VERSION 5.7 ;
BUSBITCHARS "[]" ;
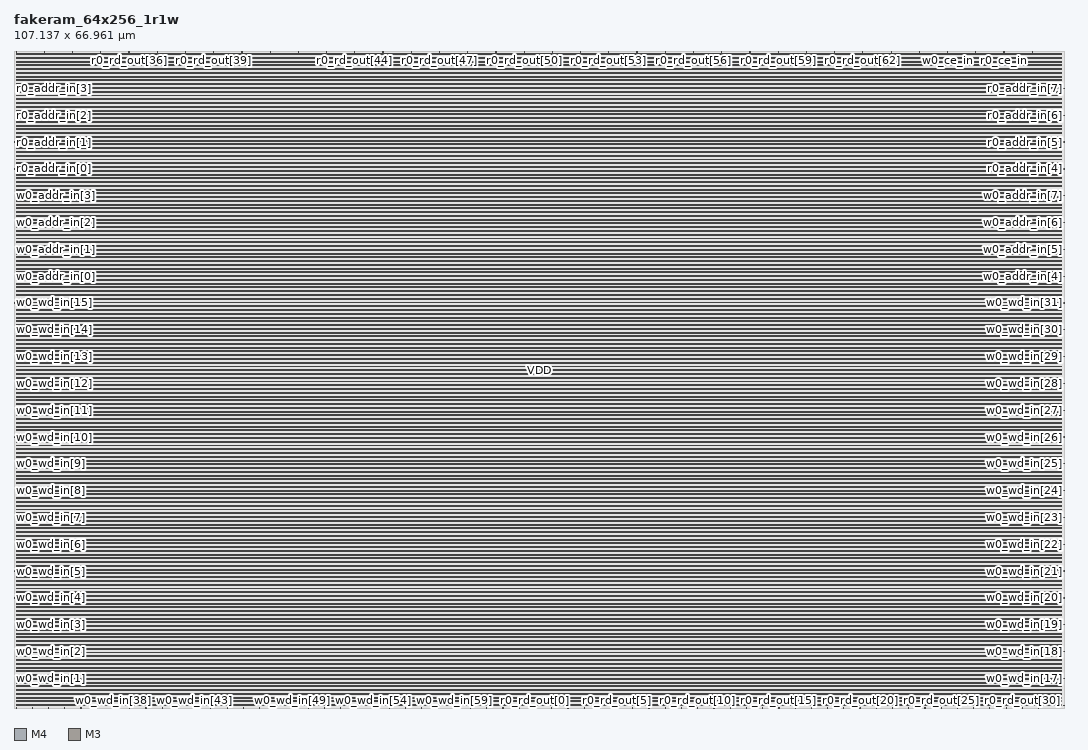
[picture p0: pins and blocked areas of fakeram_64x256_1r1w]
MACRO fakeram_64x256_1r1w
  FOREIGN fakeram_64x256_1r1w 0 0 ;
  SYMMETRY X Y R90 ;
  SIZE 107.137 BY 66.961 ;
  CLASS BLOCK ;
  PIN w0_wd_in[0]
    DIRECTION INPUT ;
    USE SIGNAL ;
    SHAPE ABUTMENT ;
    PORT
      LAYER M4 ;
      RECT 0.000 0.276 0.072 0.300 ;
    END
  END w0_wd_in[0]
  PIN w0_wd_in[1]
    DIRECTION INPUT ;
    USE SIGNAL ;
    SHAPE ABUTMENT ;
    PORT
      LAYER M4 ;
      RECT 0.000 3.012 0.072 3.036 ;
    END
  END w0_wd_in[1]
  PIN w0_wd_in[2]
    DIRECTION INPUT ;
    USE SIGNAL ;
    SHAPE ABUTMENT ;
    PORT
      LAYER M4 ;
      RECT 0.000 5.748 0.072 5.772 ;
    END
  END w0_wd_in[2]
  PIN w0_wd_in[3]
    DIRECTION INPUT ;
    USE SIGNAL ;
    SHAPE ABUTMENT ;
    PORT
      LAYER M4 ;
      RECT 0.000 8.484 0.072 8.508 ;
    END
  END w0_wd_in[3]
  PIN w0_wd_in[4]
    DIRECTION INPUT ;
    USE SIGNAL ;
    SHAPE ABUTMENT ;
    PORT
      LAYER M4 ;
      RECT 0.000 11.220 0.072 11.244 ;
    END
  END w0_wd_in[4]
  PIN w0_wd_in[5]
    DIRECTION INPUT ;
    USE SIGNAL ;
    SHAPE ABUTMENT ;
    PORT
      LAYER M4 ;
      RECT 0.000 13.956 0.072 13.980 ;
    END
  END w0_wd_in[5]
  PIN w0_wd_in[6]
    DIRECTION INPUT ;
    USE SIGNAL ;
    SHAPE ABUTMENT ;
    PORT
      LAYER M4 ;
      RECT 0.000 16.692 0.072 16.716 ;
    END
  END w0_wd_in[6]
  PIN w0_wd_in[7]
    DIRECTION INPUT ;
    USE SIGNAL ;
    SHAPE ABUTMENT ;
    PORT
      LAYER M4 ;
      RECT 0.000 19.428 0.072 19.452 ;
    END
  END w0_wd_in[7]
  PIN w0_wd_in[8]
    DIRECTION INPUT ;
    USE SIGNAL ;
    SHAPE ABUTMENT ;
    PORT
      LAYER M4 ;
      RECT 0.000 22.164 0.072 22.188 ;
    END
  END w0_wd_in[8]
  PIN w0_wd_in[9]
    DIRECTION INPUT ;
    USE SIGNAL ;
    SHAPE ABUTMENT ;
    PORT
      LAYER M4 ;
      RECT 0.000 24.900 0.072 24.924 ;
    END
  END w0_wd_in[9]
  PIN w0_wd_in[10]
    DIRECTION INPUT ;
    USE SIGNAL ;
    SHAPE ABUTMENT ;
    PORT
      LAYER M4 ;
      RECT 0.000 27.636 0.072 27.660 ;
    END
  END w0_wd_in[10]
  PIN w0_wd_in[11]
    DIRECTION INPUT ;
    USE SIGNAL ;
    SHAPE ABUTMENT ;
    PORT
      LAYER M4 ;
      RECT 0.000 30.372 0.072 30.396 ;
    END
  END w0_wd_in[11]
  PIN w0_wd_in[12]
    DIRECTION INPUT ;
    USE SIGNAL ;
    SHAPE ABUTMENT ;
    PORT
      LAYER M4 ;
      RECT 0.000 33.108 0.072 33.132 ;
    END
  END w0_wd_in[12]
  PIN w0_wd_in[13]
    DIRECTION INPUT ;
    USE SIGNAL ;
    SHAPE ABUTMENT ;
    PORT
      LAYER M4 ;
      RECT 0.000 35.844 0.072 35.868 ;
    END
  END w0_wd_in[13]
  PIN w0_wd_in[14]
    DIRECTION INPUT ;
    USE SIGNAL ;
    SHAPE ABUTMENT ;
    PORT
      LAYER M4 ;
      RECT 0.000 38.580 0.072 38.604 ;
    END
  END w0_wd_in[14]
  PIN w0_wd_in[15]
    DIRECTION INPUT ;
    USE SIGNAL ;
    SHAPE ABUTMENT ;
    PORT
      LAYER M4 ;
      RECT 0.000 41.316 0.072 41.340 ;
    END
  END w0_wd_in[15]
  PIN w0_wd_in[16]
    DIRECTION INPUT ;
    USE SIGNAL ;
    SHAPE ABUTMENT ;
    PORT
      LAYER M4 ;
      RECT 107.065 0.276 107.137 0.300 ;
    END
  END w0_wd_in[16]
  PIN w0_wd_in[17]
    DIRECTION INPUT ;
    USE SIGNAL ;
    SHAPE ABUTMENT ;
    PORT
      LAYER M4 ;
      RECT 107.065 3.012 107.137 3.036 ;
    END
  END w0_wd_in[17]
  PIN w0_wd_in[18]
    DIRECTION INPUT ;
    USE SIGNAL ;
    SHAPE ABUTMENT ;
    PORT
      LAYER M4 ;
      RECT 107.065 5.748 107.137 5.772 ;
    END
  END w0_wd_in[18]
  PIN w0_wd_in[19]
    DIRECTION INPUT ;
    USE SIGNAL ;
    SHAPE ABUTMENT ;
    PORT
      LAYER M4 ;
      RECT 107.065 8.484 107.137 8.508 ;
    END
  END w0_wd_in[19]
  PIN w0_wd_in[20]
    DIRECTION INPUT ;
    USE SIGNAL ;
    SHAPE ABUTMENT ;
    PORT
      LAYER M4 ;
      RECT 107.065 11.220 107.137 11.244 ;
    END
  END w0_wd_in[20]
  PIN w0_wd_in[21]
    DIRECTION INPUT ;
    USE SIGNAL ;
    SHAPE ABUTMENT ;
    PORT
      LAYER M4 ;
      RECT 107.065 13.956 107.137 13.980 ;
    END
  END w0_wd_in[21]
  PIN w0_wd_in[22]
    DIRECTION INPUT ;
    USE SIGNAL ;
    SHAPE ABUTMENT ;
    PORT
      LAYER M4 ;
      RECT 107.065 16.692 107.137 16.716 ;
    END
  END w0_wd_in[22]
  PIN w0_wd_in[23]
    DIRECTION INPUT ;
    USE SIGNAL ;
    SHAPE ABUTMENT ;
    PORT
      LAYER M4 ;
      RECT 107.065 19.428 107.137 19.452 ;
    END
  END w0_wd_in[23]
  PIN w0_wd_in[24]
    DIRECTION INPUT ;
    USE SIGNAL ;
    SHAPE ABUTMENT ;
    PORT
      LAYER M4 ;
      RECT 107.065 22.164 107.137 22.188 ;
    END
  END w0_wd_in[24]
  PIN w0_wd_in[25]
    DIRECTION INPUT ;
    USE SIGNAL ;
    SHAPE ABUTMENT ;
    PORT
      LAYER M4 ;
      RECT 107.065 24.900 107.137 24.924 ;
    END
  END w0_wd_in[25]
  PIN w0_wd_in[26]
    DIRECTION INPUT ;
    USE SIGNAL ;
    SHAPE ABUTMENT ;
    PORT
      LAYER M4 ;
      RECT 107.065 27.636 107.137 27.660 ;
    END
  END w0_wd_in[26]
  PIN w0_wd_in[27]
    DIRECTION INPUT ;
    USE SIGNAL ;
    SHAPE ABUTMENT ;
    PORT
      LAYER M4 ;
      RECT 107.065 30.372 107.137 30.396 ;
    END
  END w0_wd_in[27]
  PIN w0_wd_in[28]
    DIRECTION INPUT ;
    USE SIGNAL ;
    SHAPE ABUTMENT ;
    PORT
      LAYER M4 ;
      RECT 107.065 33.108 107.137 33.132 ;
    END
  END w0_wd_in[28]
  PIN w0_wd_in[29]
    DIRECTION INPUT ;
    USE SIGNAL ;
    SHAPE ABUTMENT ;
    PORT
      LAYER M4 ;
      RECT 107.065 35.844 107.137 35.868 ;
    END
  END w0_wd_in[29]
  PIN w0_wd_in[30]
    DIRECTION INPUT ;
    USE SIGNAL ;
    SHAPE ABUTMENT ;
    PORT
      LAYER M4 ;
      RECT 107.065 38.580 107.137 38.604 ;
    END
  END w0_wd_in[30]
  PIN w0_wd_in[31]
    DIRECTION INPUT ;
    USE SIGNAL ;
    SHAPE ABUTMENT ;
    PORT
      LAYER M4 ;
      RECT 107.065 41.316 107.137 41.340 ;
    END
  END w0_wd_in[31]
  PIN w0_wd_in[32]
    DIRECTION INPUT ;
    USE SIGNAL ;
    SHAPE ABUTMENT ;
    PORT
      LAYER M3 ;
      RECT 0.207 0.000 0.225 0.054 ;
    END
  END w0_wd_in[32]
  PIN w0_wd_in[33]
    DIRECTION INPUT ;
    USE SIGNAL ;
    SHAPE ABUTMENT ;
    PORT
      LAYER M3 ;
      RECT 1.863 0.000 1.881 0.054 ;
    END
  END w0_wd_in[33]
  PIN w0_wd_in[34]
    DIRECTION INPUT ;
    USE SIGNAL ;
    SHAPE ABUTMENT ;
    PORT
      LAYER M3 ;
      RECT 3.519 0.000 3.537 0.054 ;
    END
  END w0_wd_in[34]
  PIN w0_wd_in[35]
    DIRECTION INPUT ;
    USE SIGNAL ;
    SHAPE ABUTMENT ;
    PORT
      LAYER M3 ;
      RECT 5.175 0.000 5.193 0.054 ;
    END
  END w0_wd_in[35]
  PIN w0_wd_in[36]
    DIRECTION INPUT ;
    USE SIGNAL ;
    SHAPE ABUTMENT ;
    PORT
      LAYER M3 ;
      RECT 6.831 0.000 6.849 0.054 ;
    END
  END w0_wd_in[36]
  PIN w0_wd_in[37]
    DIRECTION INPUT ;
    USE SIGNAL ;
    SHAPE ABUTMENT ;
    PORT
      LAYER M3 ;
      RECT 8.487 0.000 8.505 0.054 ;
    END
  END w0_wd_in[37]
  PIN w0_wd_in[38]
    DIRECTION INPUT ;
    USE SIGNAL ;
    SHAPE ABUTMENT ;
    PORT
      LAYER M3 ;
      RECT 10.143 0.000 10.161 0.054 ;
    END
  END w0_wd_in[38]
  PIN w0_wd_in[39]
    DIRECTION INPUT ;
    USE SIGNAL ;
    SHAPE ABUTMENT ;
    PORT
      LAYER M3 ;
      RECT 11.799 0.000 11.817 0.054 ;
    END
  END w0_wd_in[39]
  PIN w0_wd_in[40]
    DIRECTION INPUT ;
    USE SIGNAL ;
    SHAPE ABUTMENT ;
    PORT
      LAYER M3 ;
      RECT 13.455 0.000 13.473 0.054 ;
    END
  END w0_wd_in[40]
  PIN w0_wd_in[41]
    DIRECTION INPUT ;
    USE SIGNAL ;
    SHAPE ABUTMENT ;
    PORT
      LAYER M3 ;
      RECT 15.111 0.000 15.129 0.054 ;
    END
  END w0_wd_in[41]
  PIN w0_wd_in[42]
    DIRECTION INPUT ;
    USE SIGNAL ;
    SHAPE ABUTMENT ;
    PORT
      LAYER M3 ;
      RECT 16.767 0.000 16.785 0.054 ;
    END
  END w0_wd_in[42]
  PIN w0_wd_in[43]
    DIRECTION INPUT ;
    USE SIGNAL ;
    SHAPE ABUTMENT ;
    PORT
      LAYER M3 ;
      RECT 18.423 0.000 18.441 0.054 ;
    END
  END w0_wd_in[43]
  PIN w0_wd_in[44]
    DIRECTION INPUT ;
    USE SIGNAL ;
    SHAPE ABUTMENT ;
    PORT
      LAYER M3 ;
      RECT 20.079 0.000 20.097 0.054 ;
    END
  END w0_wd_in[44]
  PIN w0_wd_in[45]
    DIRECTION INPUT ;
    USE SIGNAL ;
    SHAPE ABUTMENT ;
    PORT
      LAYER M3 ;
      RECT 21.735 0.000 21.753 0.054 ;
    END
  END w0_wd_in[45]
  PIN w0_wd_in[46]
    DIRECTION INPUT ;
    USE SIGNAL ;
    SHAPE ABUTMENT ;
    PORT
      LAYER M3 ;
      RECT 23.391 0.000 23.409 0.054 ;
    END
  END w0_wd_in[46]
  PIN w0_wd_in[47]
    DIRECTION INPUT ;
    USE SIGNAL ;
    SHAPE ABUTMENT ;
    PORT
      LAYER M3 ;
      RECT 25.047 0.000 25.065 0.054 ;
    END
  END w0_wd_in[47]
  PIN w0_wd_in[48]
    DIRECTION INPUT ;
    USE SIGNAL ;
    SHAPE ABUTMENT ;
    PORT
      LAYER M3 ;
      RECT 26.703 0.000 26.721 0.054 ;
    END
  END w0_wd_in[48]
  PIN w0_wd_in[49]
    DIRECTION INPUT ;
    USE SIGNAL ;
    SHAPE ABUTMENT ;
    PORT
      LAYER M3 ;
      RECT 28.359 0.000 28.377 0.054 ;
    END
  END w0_wd_in[49]
  PIN w0_wd_in[50]
    DIRECTION INPUT ;
    USE SIGNAL ;
    SHAPE ABUTMENT ;
    PORT
      LAYER M3 ;
      RECT 30.015 0.000 30.033 0.054 ;
    END
  END w0_wd_in[50]
  PIN w0_wd_in[51]
    DIRECTION INPUT ;
    USE SIGNAL ;
    SHAPE ABUTMENT ;
    PORT
      LAYER M3 ;
      RECT 31.671 0.000 31.689 0.054 ;
    END
  END w0_wd_in[51]
  PIN w0_wd_in[52]
    DIRECTION INPUT ;
    USE SIGNAL ;
    SHAPE ABUTMENT ;
    PORT
      LAYER M3 ;
      RECT 33.327 0.000 33.345 0.054 ;
    END
  END w0_wd_in[52]
  PIN w0_wd_in[53]
    DIRECTION INPUT ;
    USE SIGNAL ;
    SHAPE ABUTMENT ;
    PORT
      LAYER M3 ;
      RECT 34.983 0.000 35.001 0.054 ;
    END
  END w0_wd_in[53]
  PIN w0_wd_in[54]
    DIRECTION INPUT ;
    USE SIGNAL ;
    SHAPE ABUTMENT ;
    PORT
      LAYER M3 ;
      RECT 36.639 0.000 36.657 0.054 ;
    END
  END w0_wd_in[54]
  PIN w0_wd_in[55]
    DIRECTION INPUT ;
    USE SIGNAL ;
    SHAPE ABUTMENT ;
    PORT
      LAYER M3 ;
      RECT 38.295 0.000 38.313 0.054 ;
    END
  END w0_wd_in[55]
  PIN w0_wd_in[56]
    DIRECTION INPUT ;
    USE SIGNAL ;
    SHAPE ABUTMENT ;
    PORT
      LAYER M3 ;
      RECT 39.951 0.000 39.969 0.054 ;
    END
  END w0_wd_in[56]
  PIN w0_wd_in[57]
    DIRECTION INPUT ;
    USE SIGNAL ;
    SHAPE ABUTMENT ;
    PORT
      LAYER M3 ;
      RECT 41.607 0.000 41.625 0.054 ;
    END
  END w0_wd_in[57]
  PIN w0_wd_in[58]
    DIRECTION INPUT ;
    USE SIGNAL ;
    SHAPE ABUTMENT ;
    PORT
      LAYER M3 ;
      RECT 43.263 0.000 43.281 0.054 ;
    END
  END w0_wd_in[58]
  PIN w0_wd_in[59]
    DIRECTION INPUT ;
    USE SIGNAL ;
    SHAPE ABUTMENT ;
    PORT
      LAYER M3 ;
      RECT 44.919 0.000 44.937 0.054 ;
    END
  END w0_wd_in[59]
  PIN w0_wd_in[60]
    DIRECTION INPUT ;
    USE SIGNAL ;
    SHAPE ABUTMENT ;
    PORT
      LAYER M3 ;
      RECT 46.575 0.000 46.593 0.054 ;
    END
  END w0_wd_in[60]
  PIN w0_wd_in[61]
    DIRECTION INPUT ;
    USE SIGNAL ;
    SHAPE ABUTMENT ;
    PORT
      LAYER M3 ;
      RECT 48.231 0.000 48.249 0.054 ;
    END
  END w0_wd_in[61]
  PIN w0_wd_in[62]
    DIRECTION INPUT ;
    USE SIGNAL ;
    SHAPE ABUTMENT ;
    PORT
      LAYER M3 ;
      RECT 49.887 0.000 49.905 0.054 ;
    END
  END w0_wd_in[62]
  PIN w0_wd_in[63]
    DIRECTION INPUT ;
    USE SIGNAL ;
    SHAPE ABUTMENT ;
    PORT
      LAYER M3 ;
      RECT 51.543 0.000 51.561 0.054 ;
    END
  END w0_wd_in[63]
  PIN r0_rd_out[0]
    DIRECTION OUTPUT ;
    USE SIGNAL ;
    SHAPE ABUTMENT ;
    PORT
      LAYER M3 ;
      RECT 53.199 0.000 53.217 0.054 ;
    END
  END r0_rd_out[0]
  PIN r0_rd_out[1]
    DIRECTION OUTPUT ;
    USE SIGNAL ;
    SHAPE ABUTMENT ;
    PORT
      LAYER M3 ;
      RECT 54.855 0.000 54.873 0.054 ;
    END
  END r0_rd_out[1]
  PIN r0_rd_out[2]
    DIRECTION OUTPUT ;
    USE SIGNAL ;
    SHAPE ABUTMENT ;
    PORT
      LAYER M3 ;
      RECT 56.511 0.000 56.529 0.054 ;
    END
  END r0_rd_out[2]
  PIN r0_rd_out[3]
    DIRECTION OUTPUT ;
    USE SIGNAL ;
    SHAPE ABUTMENT ;
    PORT
      LAYER M3 ;
      RECT 58.167 0.000 58.185 0.054 ;
    END
  END r0_rd_out[3]
  PIN r0_rd_out[4]
    DIRECTION OUTPUT ;
    USE SIGNAL ;
    SHAPE ABUTMENT ;
    PORT
      LAYER M3 ;
      RECT 59.823 0.000 59.841 0.054 ;
    END
  END r0_rd_out[4]
  PIN r0_rd_out[5]
    DIRECTION OUTPUT ;
    USE SIGNAL ;
    SHAPE ABUTMENT ;
    PORT
      LAYER M3 ;
      RECT 61.479 0.000 61.497 0.054 ;
    END
  END r0_rd_out[5]
  PIN r0_rd_out[6]
    DIRECTION OUTPUT ;
    USE SIGNAL ;
    SHAPE ABUTMENT ;
    PORT
      LAYER M3 ;
      RECT 63.135 0.000 63.153 0.054 ;
    END
  END r0_rd_out[6]
  PIN r0_rd_out[7]
    DIRECTION OUTPUT ;
    USE SIGNAL ;
    SHAPE ABUTMENT ;
    PORT
      LAYER M3 ;
      RECT 64.791 0.000 64.809 0.054 ;
    END
  END r0_rd_out[7]
  PIN r0_rd_out[8]
    DIRECTION OUTPUT ;
    USE SIGNAL ;
    SHAPE ABUTMENT ;
    PORT
      LAYER M3 ;
      RECT 66.447 0.000 66.465 0.054 ;
    END
  END r0_rd_out[8]
  PIN r0_rd_out[9]
    DIRECTION OUTPUT ;
    USE SIGNAL ;
    SHAPE ABUTMENT ;
    PORT
      LAYER M3 ;
      RECT 68.103 0.000 68.121 0.054 ;
    END
  END r0_rd_out[9]
  PIN r0_rd_out[10]
    DIRECTION OUTPUT ;
    USE SIGNAL ;
    SHAPE ABUTMENT ;
    PORT
      LAYER M3 ;
      RECT 69.759 0.000 69.777 0.054 ;
    END
  END r0_rd_out[10]
  PIN r0_rd_out[11]
    DIRECTION OUTPUT ;
    USE SIGNAL ;
    SHAPE ABUTMENT ;
    PORT
      LAYER M3 ;
      RECT 71.415 0.000 71.433 0.054 ;
    END
  END r0_rd_out[11]
  PIN r0_rd_out[12]
    DIRECTION OUTPUT ;
    USE SIGNAL ;
    SHAPE ABUTMENT ;
    PORT
      LAYER M3 ;
      RECT 73.071 0.000 73.089 0.054 ;
    END
  END r0_rd_out[12]
  PIN r0_rd_out[13]
    DIRECTION OUTPUT ;
    USE SIGNAL ;
    SHAPE ABUTMENT ;
    PORT
      LAYER M3 ;
      RECT 74.727 0.000 74.745 0.054 ;
    END
  END r0_rd_out[13]
  PIN r0_rd_out[14]
    DIRECTION OUTPUT ;
    USE SIGNAL ;
    SHAPE ABUTMENT ;
    PORT
      LAYER M3 ;
      RECT 76.383 0.000 76.401 0.054 ;
    END
  END r0_rd_out[14]
  PIN r0_rd_out[15]
    DIRECTION OUTPUT ;
    USE SIGNAL ;
    SHAPE ABUTMENT ;
    PORT
      LAYER M3 ;
      RECT 78.039 0.000 78.057 0.054 ;
    END
  END r0_rd_out[15]
  PIN r0_rd_out[16]
    DIRECTION OUTPUT ;
    USE SIGNAL ;
    SHAPE ABUTMENT ;
    PORT
      LAYER M3 ;
      RECT 79.695 0.000 79.713 0.054 ;
    END
  END r0_rd_out[16]
  PIN r0_rd_out[17]
    DIRECTION OUTPUT ;
    USE SIGNAL ;
    SHAPE ABUTMENT ;
    PORT
      LAYER M3 ;
      RECT 81.351 0.000 81.369 0.054 ;
    END
  END r0_rd_out[17]
  PIN r0_rd_out[18]
    DIRECTION OUTPUT ;
    USE SIGNAL ;
    SHAPE ABUTMENT ;
    PORT
      LAYER M3 ;
      RECT 83.007 0.000 83.025 0.054 ;
    END
  END r0_rd_out[18]
  PIN r0_rd_out[19]
    DIRECTION OUTPUT ;
    USE SIGNAL ;
    SHAPE ABUTMENT ;
    PORT
      LAYER M3 ;
      RECT 84.663 0.000 84.681 0.054 ;
    END
  END r0_rd_out[19]
  PIN r0_rd_out[20]
    DIRECTION OUTPUT ;
    USE SIGNAL ;
    SHAPE ABUTMENT ;
    PORT
      LAYER M3 ;
      RECT 86.319 0.000 86.337 0.054 ;
    END
  END r0_rd_out[20]
  PIN r0_rd_out[21]
    DIRECTION OUTPUT ;
    USE SIGNAL ;
    SHAPE ABUTMENT ;
    PORT
      LAYER M3 ;
      RECT 87.975 0.000 87.993 0.054 ;
    END
  END r0_rd_out[21]
  PIN r0_rd_out[22]
    DIRECTION OUTPUT ;
    USE SIGNAL ;
    SHAPE ABUTMENT ;
    PORT
      LAYER M3 ;
      RECT 89.631 0.000 89.649 0.054 ;
    END
  END r0_rd_out[22]
  PIN r0_rd_out[23]
    DIRECTION OUTPUT ;
    USE SIGNAL ;
    SHAPE ABUTMENT ;
    PORT
      LAYER M3 ;
      RECT 91.287 0.000 91.305 0.054 ;
    END
  END r0_rd_out[23]
  PIN r0_rd_out[24]
    DIRECTION OUTPUT ;
    USE SIGNAL ;
    SHAPE ABUTMENT ;
    PORT
      LAYER M3 ;
      RECT 92.943 0.000 92.961 0.054 ;
    END
  END r0_rd_out[24]
  PIN r0_rd_out[25]
    DIRECTION OUTPUT ;
    USE SIGNAL ;
    SHAPE ABUTMENT ;
    PORT
      LAYER M3 ;
      RECT 94.599 0.000 94.617 0.054 ;
    END
  END r0_rd_out[25]
  PIN r0_rd_out[26]
    DIRECTION OUTPUT ;
    USE SIGNAL ;
    SHAPE ABUTMENT ;
    PORT
      LAYER M3 ;
      RECT 96.255 0.000 96.273 0.054 ;
    END
  END r0_rd_out[26]
  PIN r0_rd_out[27]
    DIRECTION OUTPUT ;
    USE SIGNAL ;
    SHAPE ABUTMENT ;
    PORT
      LAYER M3 ;
      RECT 97.911 0.000 97.929 0.054 ;
    END
  END r0_rd_out[27]
  PIN r0_rd_out[28]
    DIRECTION OUTPUT ;
    USE SIGNAL ;
    SHAPE ABUTMENT ;
    PORT
      LAYER M3 ;
      RECT 99.567 0.000 99.585 0.054 ;
    END
  END r0_rd_out[28]
  PIN r0_rd_out[29]
    DIRECTION OUTPUT ;
    USE SIGNAL ;
    SHAPE ABUTMENT ;
    PORT
      LAYER M3 ;
      RECT 101.223 0.000 101.241 0.054 ;
    END
  END r0_rd_out[29]
  PIN r0_rd_out[30]
    DIRECTION OUTPUT ;
    USE SIGNAL ;
    SHAPE ABUTMENT ;
    PORT
      LAYER M3 ;
      RECT 102.879 0.000 102.897 0.054 ;
    END
  END r0_rd_out[30]
  PIN r0_rd_out[31]
    DIRECTION OUTPUT ;
    USE SIGNAL ;
    SHAPE ABUTMENT ;
    PORT
      LAYER M3 ;
      RECT 104.535 0.000 104.553 0.054 ;
    END
  END r0_rd_out[31]
  PIN r0_rd_out[32]
    DIRECTION OUTPUT ;
    USE SIGNAL ;
    SHAPE ABUTMENT ;
    PORT
      LAYER M3 ;
      RECT 0.207 66.907 0.225 66.961 ;
    END
  END r0_rd_out[32]
  PIN r0_rd_out[33]
    DIRECTION OUTPUT ;
    USE SIGNAL ;
    SHAPE ABUTMENT ;
    PORT
      LAYER M3 ;
      RECT 3.087 66.907 3.105 66.961 ;
    END
  END r0_rd_out[33]
  PIN r0_rd_out[34]
    DIRECTION OUTPUT ;
    USE SIGNAL ;
    SHAPE ABUTMENT ;
    PORT
      LAYER M3 ;
      RECT 5.967 66.907 5.985 66.961 ;
    END
  END r0_rd_out[34]
  PIN r0_rd_out[35]
    DIRECTION OUTPUT ;
    USE SIGNAL ;
    SHAPE ABUTMENT ;
    PORT
      LAYER M3 ;
      RECT 8.847 66.907 8.865 66.961 ;
    END
  END r0_rd_out[35]
  PIN r0_rd_out[36]
    DIRECTION OUTPUT ;
    USE SIGNAL ;
    SHAPE ABUTMENT ;
    PORT
      LAYER M3 ;
      RECT 11.727 66.907 11.745 66.961 ;
    END
  END r0_rd_out[36]
  PIN r0_rd_out[37]
    DIRECTION OUTPUT ;
    USE SIGNAL ;
    SHAPE ABUTMENT ;
    PORT
      LAYER M3 ;
      RECT 14.607 66.907 14.625 66.961 ;
    END
  END r0_rd_out[37]
  PIN r0_rd_out[38]
    DIRECTION OUTPUT ;
    USE SIGNAL ;
    SHAPE ABUTMENT ;
    PORT
      LAYER M3 ;
      RECT 17.487 66.907 17.505 66.961 ;
    END
  END r0_rd_out[38]
  PIN r0_rd_out[39]
    DIRECTION OUTPUT ;
    USE SIGNAL ;
    SHAPE ABUTMENT ;
    PORT
      LAYER M3 ;
      RECT 20.367 66.907 20.385 66.961 ;
    END
  END r0_rd_out[39]
  PIN r0_rd_out[40]
    DIRECTION OUTPUT ;
    USE SIGNAL ;
    SHAPE ABUTMENT ;
    PORT
      LAYER M3 ;
      RECT 23.247 66.907 23.265 66.961 ;
    END
  END r0_rd_out[40]
  PIN r0_rd_out[41]
    DIRECTION OUTPUT ;
    USE SIGNAL ;
    SHAPE ABUTMENT ;
    PORT
      LAYER M3 ;
      RECT 26.127 66.907 26.145 66.961 ;
    END
  END r0_rd_out[41]
  PIN r0_rd_out[42]
    DIRECTION OUTPUT ;
    USE SIGNAL ;
    SHAPE ABUTMENT ;
    PORT
      LAYER M3 ;
      RECT 29.007 66.907 29.025 66.961 ;
    END
  END r0_rd_out[42]
  PIN r0_rd_out[43]
    DIRECTION OUTPUT ;
    USE SIGNAL ;
    SHAPE ABUTMENT ;
    PORT
      LAYER M3 ;
      RECT 31.887 66.907 31.905 66.961 ;
    END
  END r0_rd_out[43]
  PIN r0_rd_out[44]
    DIRECTION OUTPUT ;
    USE SIGNAL ;
    SHAPE ABUTMENT ;
    PORT
      LAYER M3 ;
      RECT 34.767 66.907 34.785 66.961 ;
    END
  END r0_rd_out[44]
  PIN r0_rd_out[45]
    DIRECTION OUTPUT ;
    USE SIGNAL ;
    SHAPE ABUTMENT ;
    PORT
      LAYER M3 ;
      RECT 37.647 66.907 37.665 66.961 ;
    END
  END r0_rd_out[45]
  PIN r0_rd_out[46]
    DIRECTION OUTPUT ;
    USE SIGNAL ;
    SHAPE ABUTMENT ;
    PORT
      LAYER M3 ;
      RECT 40.527 66.907 40.545 66.961 ;
    END
  END r0_rd_out[46]
  PIN r0_rd_out[47]
    DIRECTION OUTPUT ;
    USE SIGNAL ;
    SHAPE ABUTMENT ;
    PORT
      LAYER M3 ;
      RECT 43.407 66.907 43.425 66.961 ;
    END
  END r0_rd_out[47]
  PIN r0_rd_out[48]
    DIRECTION OUTPUT ;
    USE SIGNAL ;
    SHAPE ABUTMENT ;
    PORT
      LAYER M3 ;
      RECT 46.287 66.907 46.305 66.961 ;
    END
  END r0_rd_out[48]
  PIN r0_rd_out[49]
    DIRECTION OUTPUT ;
    USE SIGNAL ;
    SHAPE ABUTMENT ;
    PORT
      LAYER M3 ;
      RECT 49.167 66.907 49.185 66.961 ;
    END
  END r0_rd_out[49]
  PIN r0_rd_out[50]
    DIRECTION OUTPUT ;
    USE SIGNAL ;
    SHAPE ABUTMENT ;
    PORT
      LAYER M3 ;
      RECT 52.047 66.907 52.065 66.961 ;
    END
  END r0_rd_out[50]
  PIN r0_rd_out[51]
    DIRECTION OUTPUT ;
    USE SIGNAL ;
    SHAPE ABUTMENT ;
    PORT
      LAYER M3 ;
      RECT 54.927 66.907 54.945 66.961 ;
    END
  END r0_rd_out[51]
  PIN r0_rd_out[52]
    DIRECTION OUTPUT ;
    USE SIGNAL ;
    SHAPE ABUTMENT ;
    PORT
      LAYER M3 ;
      RECT 57.807 66.907 57.825 66.961 ;
    END
  END r0_rd_out[52]
  PIN r0_rd_out[53]
    DIRECTION OUTPUT ;
    USE SIGNAL ;
    SHAPE ABUTMENT ;
    PORT
      LAYER M3 ;
      RECT 60.687 66.907 60.705 66.961 ;
    END
  END r0_rd_out[53]
  PIN r0_rd_out[54]
    DIRECTION OUTPUT ;
    USE SIGNAL ;
    SHAPE ABUTMENT ;
    PORT
      LAYER M3 ;
      RECT 63.567 66.907 63.585 66.961 ;
    END
  END r0_rd_out[54]
  PIN r0_rd_out[55]
    DIRECTION OUTPUT ;
    USE SIGNAL ;
    SHAPE ABUTMENT ;
    PORT
      LAYER M3 ;
      RECT 66.447 66.907 66.465 66.961 ;
    END
  END r0_rd_out[55]
  PIN r0_rd_out[56]
    DIRECTION OUTPUT ;
    USE SIGNAL ;
    SHAPE ABUTMENT ;
    PORT
      LAYER M3 ;
      RECT 69.327 66.907 69.345 66.961 ;
    END
  END r0_rd_out[56]
  PIN r0_rd_out[57]
    DIRECTION OUTPUT ;
    USE SIGNAL ;
    SHAPE ABUTMENT ;
    PORT
      LAYER M3 ;
      RECT 72.207 66.907 72.225 66.961 ;
    END
  END r0_rd_out[57]
  PIN r0_rd_out[58]
    DIRECTION OUTPUT ;
    USE SIGNAL ;
    SHAPE ABUTMENT ;
    PORT
      LAYER M3 ;
      RECT 75.087 66.907 75.105 66.961 ;
    END
  END r0_rd_out[58]
  PIN r0_rd_out[59]
    DIRECTION OUTPUT ;
    USE SIGNAL ;
    SHAPE ABUTMENT ;
    PORT
      LAYER M3 ;
      RECT 77.967 66.907 77.985 66.961 ;
    END
  END r0_rd_out[59]
  PIN r0_rd_out[60]
    DIRECTION OUTPUT ;
    USE SIGNAL ;
    SHAPE ABUTMENT ;
    PORT
      LAYER M3 ;
      RECT 80.847 66.907 80.865 66.961 ;
    END
  END r0_rd_out[60]
  PIN r0_rd_out[61]
    DIRECTION OUTPUT ;
    USE SIGNAL ;
    SHAPE ABUTMENT ;
    PORT
      LAYER M3 ;
      RECT 83.727 66.907 83.745 66.961 ;
    END
  END r0_rd_out[61]
  PIN r0_rd_out[62]
    DIRECTION OUTPUT ;
    USE SIGNAL ;
    SHAPE ABUTMENT ;
    PORT
      LAYER M3 ;
      RECT 86.607 66.907 86.625 66.961 ;
    END
  END r0_rd_out[62]
  PIN r0_rd_out[63]
    DIRECTION OUTPUT ;
    USE SIGNAL ;
    SHAPE ABUTMENT ;
    PORT
      LAYER M3 ;
      RECT 89.487 66.907 89.505 66.961 ;
    END
  END r0_rd_out[63]
  PIN w0_addr_in[0]
    DIRECTION INPUT ;
    USE SIGNAL ;
    SHAPE ABUTMENT ;
    PORT
      LAYER M4 ;
      RECT 0.000 44.052 0.072 44.076 ;
    END
  END w0_addr_in[0]
  PIN w0_addr_in[1]
    DIRECTION INPUT ;
    USE SIGNAL ;
    SHAPE ABUTMENT ;
    PORT
      LAYER M4 ;
      RECT 0.000 46.788 0.072 46.812 ;
    END
  END w0_addr_in[1]
  PIN w0_addr_in[2]
    DIRECTION INPUT ;
    USE SIGNAL ;
    SHAPE ABUTMENT ;
    PORT
      LAYER M4 ;
      RECT 0.000 49.524 0.072 49.548 ;
    END
  END w0_addr_in[2]
  PIN w0_addr_in[3]
    DIRECTION INPUT ;
    USE SIGNAL ;
    SHAPE ABUTMENT ;
    PORT
      LAYER M4 ;
      RECT 0.000 52.260 0.072 52.284 ;
    END
  END w0_addr_in[3]
  PIN w0_addr_in[4]
    DIRECTION INPUT ;
    USE SIGNAL ;
    SHAPE ABUTMENT ;
    PORT
      LAYER M4 ;
      RECT 107.065 44.052 107.137 44.076 ;
    END
  END w0_addr_in[4]
  PIN w0_addr_in[5]
    DIRECTION INPUT ;
    USE SIGNAL ;
    SHAPE ABUTMENT ;
    PORT
      LAYER M4 ;
      RECT 107.065 46.788 107.137 46.812 ;
    END
  END w0_addr_in[5]
  PIN w0_addr_in[6]
    DIRECTION INPUT ;
    USE SIGNAL ;
    SHAPE ABUTMENT ;
    PORT
      LAYER M4 ;
      RECT 107.065 49.524 107.137 49.548 ;
    END
  END w0_addr_in[6]
  PIN w0_addr_in[7]
    DIRECTION INPUT ;
    USE SIGNAL ;
    SHAPE ABUTMENT ;
    PORT
      LAYER M4 ;
      RECT 107.065 52.260 107.137 52.284 ;
    END
  END w0_addr_in[7]
  PIN r0_addr_in[0]
    DIRECTION INPUT ;
    USE SIGNAL ;
    SHAPE ABUTMENT ;
    PORT
      LAYER M4 ;
      RECT 0.000 54.996 0.072 55.020 ;
    END
  END r0_addr_in[0]
  PIN r0_addr_in[1]
    DIRECTION INPUT ;
    USE SIGNAL ;
    SHAPE ABUTMENT ;
    PORT
      LAYER M4 ;
      RECT 0.000 57.732 0.072 57.756 ;
    END
  END r0_addr_in[1]
  PIN r0_addr_in[2]
    DIRECTION INPUT ;
    USE SIGNAL ;
    SHAPE ABUTMENT ;
    PORT
      LAYER M4 ;
      RECT 0.000 60.468 0.072 60.492 ;
    END
  END r0_addr_in[2]
  PIN r0_addr_in[3]
    DIRECTION INPUT ;
    USE SIGNAL ;
    SHAPE ABUTMENT ;
    PORT
      LAYER M4 ;
      RECT 0.000 63.204 0.072 63.228 ;
    END
  END r0_addr_in[3]
  PIN r0_addr_in[4]
    DIRECTION INPUT ;
    USE SIGNAL ;
    SHAPE ABUTMENT ;
    PORT
      LAYER M4 ;
      RECT 107.065 54.996 107.137 55.020 ;
    END
  END r0_addr_in[4]
  PIN r0_addr_in[5]
    DIRECTION INPUT ;
    USE SIGNAL ;
    SHAPE ABUTMENT ;
    PORT
      LAYER M4 ;
      RECT 107.065 57.732 107.137 57.756 ;
    END
  END r0_addr_in[5]
  PIN r0_addr_in[6]
    DIRECTION INPUT ;
    USE SIGNAL ;
    SHAPE ABUTMENT ;
    PORT
      LAYER M4 ;
      RECT 107.065 60.468 107.137 60.492 ;
    END
  END r0_addr_in[6]
  PIN r0_addr_in[7]
    DIRECTION INPUT ;
    USE SIGNAL ;
    SHAPE ABUTMENT ;
    PORT
      LAYER M4 ;
      RECT 107.065 63.204 107.137 63.228 ;
    END
  END r0_addr_in[7]
  PIN w0_we_in
    DIRECTION INPUT ;
    USE SIGNAL ;
    SHAPE ABUTMENT ;
    PORT
      LAYER M3 ;
      RECT 92.367 66.907 92.385 66.961 ;
    END
  END w0_we_in
  PIN w0_ce_in
    DIRECTION INPUT ;
    USE SIGNAL ;
    SHAPE ABUTMENT ;
    PORT
      LAYER M3 ;
      RECT 95.247 66.907 95.265 66.961 ;
    END
  END w0_ce_in
  PIN w0_clk
    DIRECTION INPUT ;
    USE SIGNAL ;
    SHAPE ABUTMENT ;
    PORT
      LAYER M3 ;
      RECT 98.127 66.907 98.145 66.961 ;
    END
  END w0_clk
  PIN r0_ce_in
    DIRECTION INPUT ;
    USE SIGNAL ;
    SHAPE ABUTMENT ;
    PORT
      LAYER M3 ;
      RECT 101.007 66.907 101.025 66.961 ;
    END
  END r0_ce_in
  PIN r0_clk
    DIRECTION INPUT ;
    USE SIGNAL ;
    SHAPE ABUTMENT ;
    PORT
      LAYER M3 ;
      RECT 103.887 66.907 103.905 66.961 ;
    END
  END r0_clk
  PIN VSS
    DIRECTION INOUT ;
    USE GROUND ;
    PORT
      LAYER M4 ;
      RECT 0.216 0.240 106.921 0.336 ;
      RECT 0.216 1.008 106.921 1.104 ;
      RECT 0.216 1.776 106.921 1.872 ;
      RECT 0.216 2.544 106.921 2.640 ;
      RECT 0.216 3.312 106.921 3.408 ;
      RECT 0.216 4.080 106.921 4.176 ;
      RECT 0.216 4.848 106.921 4.944 ;
      RECT 0.216 5.616 106.921 5.712 ;
      RECT 0.216 6.384 106.921 6.480 ;
      RECT 0.216 7.152 106.921 7.248 ;
      RECT 0.216 7.920 106.921 8.016 ;
      RECT 0.216 8.688 106.921 8.784 ;
      RECT 0.216 9.456 106.921 9.552 ;
      RECT 0.216 10.224 106.921 10.320 ;
      RECT 0.216 10.992 106.921 11.088 ;
      RECT 0.216 11.760 106.921 11.856 ;
      RECT 0.216 12.528 106.921 12.624 ;
      RECT 0.216 13.296 106.921 13.392 ;
      RECT 0.216 14.064 106.921 14.160 ;
      RECT 0.216 14.832 106.921 14.928 ;
      RECT 0.216 15.600 106.921 15.696 ;
      RECT 0.216 16.368 106.921 16.464 ;
      RECT 0.216 17.136 106.921 17.232 ;
      RECT 0.216 17.904 106.921 18.000 ;
      RECT 0.216 18.672 106.921 18.768 ;
      RECT 0.216 19.440 106.921 19.536 ;
      RECT 0.216 20.208 106.921 20.304 ;
      RECT 0.216 20.976 106.921 21.072 ;
      RECT 0.216 21.744 106.921 21.840 ;
      RECT 0.216 22.512 106.921 22.608 ;
      RECT 0.216 23.280 106.921 23.376 ;
      RECT 0.216 24.048 106.921 24.144 ;
      RECT 0.216 24.816 106.921 24.912 ;
      RECT 0.216 25.584 106.921 25.680 ;
      RECT 0.216 26.352 106.921 26.448 ;
      RECT 0.216 27.120 106.921 27.216 ;
      RECT 0.216 27.888 106.921 27.984 ;
      RECT 0.216 28.656 106.921 28.752 ;
      RECT 0.216 29.424 106.921 29.520 ;
      RECT 0.216 30.192 106.921 30.288 ;
      RECT 0.216 30.960 106.921 31.056 ;
      RECT 0.216 31.728 106.921 31.824 ;
      RECT 0.216 32.496 106.921 32.592 ;
      RECT 0.216 33.264 106.921 33.360 ;
      RECT 0.216 34.032 106.921 34.128 ;
      RECT 0.216 34.800 106.921 34.896 ;
      RECT 0.216 35.568 106.921 35.664 ;
      RECT 0.216 36.336 106.921 36.432 ;
      RECT 0.216 37.104 106.921 37.200 ;
      RECT 0.216 37.872 106.921 37.968 ;
      RECT 0.216 38.640 106.921 38.736 ;
      RECT 0.216 39.408 106.921 39.504 ;
      RECT 0.216 40.176 106.921 40.272 ;
      RECT 0.216 40.944 106.921 41.040 ;
      RECT 0.216 41.712 106.921 41.808 ;
      RECT 0.216 42.480 106.921 42.576 ;
      RECT 0.216 43.248 106.921 43.344 ;
      RECT 0.216 44.016 106.921 44.112 ;
      RECT 0.216 44.784 106.921 44.880 ;
      RECT 0.216 45.552 106.921 45.648 ;
      RECT 0.216 46.320 106.921 46.416 ;
      RECT 0.216 47.088 106.921 47.184 ;
      RECT 0.216 47.856 106.921 47.952 ;
      RECT 0.216 48.624 106.921 48.720 ;
      RECT 0.216 49.392 106.921 49.488 ;
      RECT 0.216 50.160 106.921 50.256 ;
      RECT 0.216 50.928 106.921 51.024 ;
      RECT 0.216 51.696 106.921 51.792 ;
      RECT 0.216 52.464 106.921 52.560 ;
      RECT 0.216 53.232 106.921 53.328 ;
      RECT 0.216 54.000 106.921 54.096 ;
      RECT 0.216 54.768 106.921 54.864 ;
      RECT 0.216 55.536 106.921 55.632 ;
      RECT 0.216 56.304 106.921 56.400 ;
      RECT 0.216 57.072 106.921 57.168 ;
      RECT 0.216 57.840 106.921 57.936 ;
      RECT 0.216 58.608 106.921 58.704 ;
      RECT 0.216 59.376 106.921 59.472 ;
      RECT 0.216 60.144 106.921 60.240 ;
      RECT 0.216 60.912 106.921 61.008 ;
      RECT 0.216 61.680 106.921 61.776 ;
      RECT 0.216 62.448 106.921 62.544 ;
      RECT 0.216 63.216 106.921 63.312 ;
      RECT 0.216 63.984 106.921 64.080 ;
      RECT 0.216 64.752 106.921 64.848 ;
      RECT 0.216 65.520 106.921 65.616 ;
      RECT 0.216 66.288 106.921 66.384 ;
    END
  END VSS
  PIN VDD
    DIRECTION INOUT ;
    USE POWER ;
    PORT
      LAYER M4 ;
      RECT 0.216 0.624 106.921 0.720 ;
      RECT 0.216 1.392 106.921 1.488 ;
      RECT 0.216 2.160 106.921 2.256 ;
      RECT 0.216 2.928 106.921 3.024 ;
      RECT 0.216 3.696 106.921 3.792 ;
      RECT 0.216 4.464 106.921 4.560 ;
      RECT 0.216 5.232 106.921 5.328 ;
      RECT 0.216 6.000 106.921 6.096 ;
      RECT 0.216 6.768 106.921 6.864 ;
      RECT 0.216 7.536 106.921 7.632 ;
      RECT 0.216 8.304 106.921 8.400 ;
      RECT 0.216 9.072 106.921 9.168 ;
      RECT 0.216 9.840 106.921 9.936 ;
      RECT 0.216 10.608 106.921 10.704 ;
      RECT 0.216 11.376 106.921 11.472 ;
      RECT 0.216 12.144 106.921 12.240 ;
      RECT 0.216 12.912 106.921 13.008 ;
      RECT 0.216 13.680 106.921 13.776 ;
      RECT 0.216 14.448 106.921 14.544 ;
      RECT 0.216 15.216 106.921 15.312 ;
      RECT 0.216 15.984 106.921 16.080 ;
      RECT 0.216 16.752 106.921 16.848 ;
      RECT 0.216 17.520 106.921 17.616 ;
      RECT 0.216 18.288 106.921 18.384 ;
      RECT 0.216 19.056 106.921 19.152 ;
      RECT 0.216 19.824 106.921 19.920 ;
      RECT 0.216 20.592 106.921 20.688 ;
      RECT 0.216 21.360 106.921 21.456 ;
      RECT 0.216 22.128 106.921 22.224 ;
      RECT 0.216 22.896 106.921 22.992 ;
      RECT 0.216 23.664 106.921 23.760 ;
      RECT 0.216 24.432 106.921 24.528 ;
      RECT 0.216 25.200 106.921 25.296 ;
      RECT 0.216 25.968 106.921 26.064 ;
      RECT 0.216 26.736 106.921 26.832 ;
      RECT 0.216 27.504 106.921 27.600 ;
      RECT 0.216 28.272 106.921 28.368 ;
      RECT 0.216 29.040 106.921 29.136 ;
      RECT 0.216 29.808 106.921 29.904 ;
      RECT 0.216 30.576 106.921 30.672 ;
      RECT 0.216 31.344 106.921 31.440 ;
      RECT 0.216 32.112 106.921 32.208 ;
      RECT 0.216 32.880 106.921 32.976 ;
      RECT 0.216 33.648 106.921 33.744 ;
      RECT 0.216 34.416 106.921 34.512 ;
      RECT 0.216 35.184 106.921 35.280 ;
      RECT 0.216 35.952 106.921 36.048 ;
      RECT 0.216 36.720 106.921 36.816 ;
      RECT 0.216 37.488 106.921 37.584 ;
      RECT 0.216 38.256 106.921 38.352 ;
      RECT 0.216 39.024 106.921 39.120 ;
      RECT 0.216 39.792 106.921 39.888 ;
      RECT 0.216 40.560 106.921 40.656 ;
      RECT 0.216 41.328 106.921 41.424 ;
      RECT 0.216 42.096 106.921 42.192 ;
      RECT 0.216 42.864 106.921 42.960 ;
      RECT 0.216 43.632 106.921 43.728 ;
      RECT 0.216 44.400 106.921 44.496 ;
      RECT 0.216 45.168 106.921 45.264 ;
      RECT 0.216 45.936 106.921 46.032 ;
      RECT 0.216 46.704 106.921 46.800 ;
      RECT 0.216 47.472 106.921 47.568 ;
      RECT 0.216 48.240 106.921 48.336 ;
      RECT 0.216 49.008 106.921 49.104 ;
      RECT 0.216 49.776 106.921 49.872 ;
      RECT 0.216 50.544 106.921 50.640 ;
      RECT 0.216 51.312 106.921 51.408 ;
      RECT 0.216 52.080 106.921 52.176 ;
      RECT 0.216 52.848 106.921 52.944 ;
      RECT 0.216 53.616 106.921 53.712 ;
      RECT 0.216 54.384 106.921 54.480 ;
      RECT 0.216 55.152 106.921 55.248 ;
      RECT 0.216 55.920 106.921 56.016 ;
      RECT 0.216 56.688 106.921 56.784 ;
      RECT 0.216 57.456 106.921 57.552 ;
      RECT 0.216 58.224 106.921 58.320 ;
      RECT 0.216 58.992 106.921 59.088 ;
      RECT 0.216 59.760 106.921 59.856 ;
      RECT 0.216 60.528 106.921 60.624 ;
      RECT 0.216 61.296 106.921 61.392 ;
      RECT 0.216 62.064 106.921 62.160 ;
      RECT 0.216 62.832 106.921 62.928 ;
      RECT 0.216 63.600 106.921 63.696 ;
      RECT 0.216 64.368 106.921 64.464 ;
      RECT 0.216 65.136 106.921 65.232 ;
      RECT 0.216 65.904 106.921 66.000 ;
      RECT 0.216 66.672 106.921 66.768 ;
    END
  END VDD
  OBS
    LAYER M1 ;
    RECT 0 0 107.137 66.961 ;
    LAYER M2 ;
    RECT 0 0 107.137 66.961 ;
    LAYER M3 ;
    RECT 0 0 107.137 66.961 ;
    LAYER M4 ;
    RECT 0 0 107.137 66.961 ;
  END
END fakeram_64x256_1r1w

END LIBRARY
